VERSION 5.7 ;
  NOWIREEXTENSIONATPIN ON ;
  DIVIDERCHAR "/" ;
  BUSBITCHARS "[]" ;
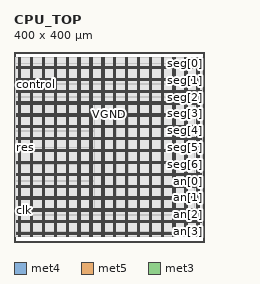
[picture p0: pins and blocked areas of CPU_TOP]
MACRO CPU_TOP
  CLASS BLOCK ;
  FOREIGN CPU_TOP ;
  ORIGIN 0.000 0.000 ;
  SIZE 400.000 BY 400.000 ;
  PIN VGND
    DIRECTION INOUT ;
    USE GROUND ;
    PORT
      LAYER met4 ;
        RECT 13.020 10.640 14.620 389.200 ;
    END
    PORT
      LAYER met4 ;
        RECT 38.020 10.640 39.620 389.200 ;
    END
    PORT
      LAYER met4 ;
        RECT 63.020 10.640 64.620 389.200 ;
    END
    PORT
      LAYER met4 ;
        RECT 88.020 10.640 89.620 389.200 ;
    END
    PORT
      LAYER met4 ;
        RECT 113.020 10.640 114.620 389.200 ;
    END
    PORT
      LAYER met4 ;
        RECT 138.020 10.640 139.620 389.200 ;
    END
    PORT
      LAYER met4 ;
        RECT 163.020 10.640 164.620 389.200 ;
    END
    PORT
      LAYER met4 ;
        RECT 188.020 10.640 189.620 389.200 ;
    END
    PORT
      LAYER met4 ;
        RECT 213.020 10.640 214.620 389.200 ;
    END
    PORT
      LAYER met4 ;
        RECT 238.020 10.640 239.620 389.200 ;
    END
    PORT
      LAYER met4 ;
        RECT 263.020 10.640 264.620 389.200 ;
    END
    PORT
      LAYER met4 ;
        RECT 288.020 10.640 289.620 389.200 ;
    END
    PORT
      LAYER met4 ;
        RECT 313.020 10.640 314.620 389.200 ;
    END
    PORT
      LAYER met4 ;
        RECT 338.020 10.640 339.620 389.200 ;
    END
    PORT
      LAYER met4 ;
        RECT 363.020 10.640 364.620 389.200 ;
    END
    PORT
      LAYER met4 ;
        RECT 388.020 10.640 389.620 389.200 ;
    END
    PORT
      LAYER met5 ;
        RECT 5.280 18.380 394.460 19.980 ;
    END
    PORT
      LAYER met5 ;
        RECT 5.280 43.380 394.460 44.980 ;
    END
    PORT
      LAYER met5 ;
        RECT 5.280 68.380 394.460 69.980 ;
    END
    PORT
      LAYER met5 ;
        RECT 5.280 93.380 394.460 94.980 ;
    END
    PORT
      LAYER met5 ;
        RECT 5.280 118.380 394.460 119.980 ;
    END
    PORT
      LAYER met5 ;
        RECT 5.280 143.380 394.460 144.980 ;
    END
    PORT
      LAYER met5 ;
        RECT 5.280 168.380 394.460 169.980 ;
    END
    PORT
      LAYER met5 ;
        RECT 5.280 193.380 394.460 194.980 ;
    END
    PORT
      LAYER met5 ;
        RECT 5.280 218.380 394.460 219.980 ;
    END
    PORT
      LAYER met5 ;
        RECT 5.280 243.380 394.460 244.980 ;
    END
    PORT
      LAYER met5 ;
        RECT 5.280 268.380 394.460 269.980 ;
    END
    PORT
      LAYER met5 ;
        RECT 5.280 293.380 394.460 294.980 ;
    END
    PORT
      LAYER met5 ;
        RECT 5.280 318.380 394.460 319.980 ;
    END
    PORT
      LAYER met5 ;
        RECT 5.280 343.380 394.460 344.980 ;
    END
    PORT
      LAYER met5 ;
        RECT 5.280 368.380 394.460 369.980 ;
    END
  END VGND
  PIN VPWR
    DIRECTION INOUT ;
    USE POWER ;
    PORT
      LAYER met4 ;
        RECT 9.720 10.640 11.320 389.200 ;
    END
    PORT
      LAYER met4 ;
        RECT 34.720 10.640 36.320 389.200 ;
    END
    PORT
      LAYER met4 ;
        RECT 59.720 10.640 61.320 389.200 ;
    END
    PORT
      LAYER met4 ;
        RECT 84.720 10.640 86.320 389.200 ;
    END
    PORT
      LAYER met4 ;
        RECT 109.720 10.640 111.320 389.200 ;
    END
    PORT
      LAYER met4 ;
        RECT 134.720 10.640 136.320 389.200 ;
    END
    PORT
      LAYER met4 ;
        RECT 159.720 10.640 161.320 389.200 ;
    END
    PORT
      LAYER met4 ;
        RECT 184.720 10.640 186.320 389.200 ;
    END
    PORT
      LAYER met4 ;
        RECT 209.720 10.640 211.320 389.200 ;
    END
    PORT
      LAYER met4 ;
        RECT 234.720 10.640 236.320 389.200 ;
    END
    PORT
      LAYER met4 ;
        RECT 259.720 10.640 261.320 389.200 ;
    END
    PORT
      LAYER met4 ;
        RECT 284.720 10.640 286.320 389.200 ;
    END
    PORT
      LAYER met4 ;
        RECT 309.720 10.640 311.320 389.200 ;
    END
    PORT
      LAYER met4 ;
        RECT 334.720 10.640 336.320 389.200 ;
    END
    PORT
      LAYER met4 ;
        RECT 359.720 10.640 361.320 389.200 ;
    END
    PORT
      LAYER met4 ;
        RECT 384.720 10.640 386.320 389.200 ;
    END
    PORT
      LAYER met5 ;
        RECT 5.280 15.080 394.460 16.680 ;
    END
    PORT
      LAYER met5 ;
        RECT 5.280 40.080 394.460 41.680 ;
    END
    PORT
      LAYER met5 ;
        RECT 5.280 65.080 394.460 66.680 ;
    END
    PORT
      LAYER met5 ;
        RECT 5.280 90.080 394.460 91.680 ;
    END
    PORT
      LAYER met5 ;
        RECT 5.280 115.080 394.460 116.680 ;
    END
    PORT
      LAYER met5 ;
        RECT 5.280 140.080 394.460 141.680 ;
    END
    PORT
      LAYER met5 ;
        RECT 5.280 165.080 394.460 166.680 ;
    END
    PORT
      LAYER met5 ;
        RECT 5.280 190.080 394.460 191.680 ;
    END
    PORT
      LAYER met5 ;
        RECT 5.280 215.080 394.460 216.680 ;
    END
    PORT
      LAYER met5 ;
        RECT 5.280 240.080 394.460 241.680 ;
    END
    PORT
      LAYER met5 ;
        RECT 5.280 265.080 394.460 266.680 ;
    END
    PORT
      LAYER met5 ;
        RECT 5.280 290.080 394.460 291.680 ;
    END
    PORT
      LAYER met5 ;
        RECT 5.280 315.080 394.460 316.680 ;
    END
    PORT
      LAYER met5 ;
        RECT 5.280 340.080 394.460 341.680 ;
    END
    PORT
      LAYER met5 ;
        RECT 5.280 365.080 394.460 366.680 ;
    END
  END VPWR
  PIN an[0]
    DIRECTION OUTPUT ;
    USE SIGNAL ;
    ANTENNADIFFAREA 0.340600 ;
    PORT
      LAYER met3 ;
        RECT 396.000 127.880 400.000 128.480 ;
    END
  END an[0]
  PIN an[1]
    DIRECTION OUTPUT ;
    USE SIGNAL ;
    ANTENNADIFFAREA 0.340600 ;
    PORT
      LAYER met3 ;
        RECT 396.000 92.520 400.000 93.120 ;
    END
  END an[1]
  PIN an[2]
    DIRECTION OUTPUT ;
    USE SIGNAL ;
    ANTENNADIFFAREA 0.340600 ;
    PORT
      LAYER met3 ;
        RECT 396.000 57.160 400.000 57.760 ;
    END
  END an[2]
  PIN an[3]
    DIRECTION OUTPUT ;
    USE SIGNAL ;
    ANTENNADIFFAREA 0.340600 ;
    PORT
      LAYER met3 ;
        RECT 396.000 21.800 400.000 22.400 ;
    END
  END an[3]
  PIN clk
    DIRECTION INPUT ;
    USE SIGNAL ;
    ANTENNAGATEAREA 0.852000 ;
    PORT
      LAYER met3 ;
        RECT 0.000 65.320 4.000 65.920 ;
    END
  END clk
  PIN control
    DIRECTION INPUT ;
    USE SIGNAL ;
    ANTENNAGATEAREA 0.159000 ;
    PORT
      LAYER met3 ;
        RECT 0.000 331.880 4.000 332.480 ;
    END
  END control
  PIN res
    DIRECTION INPUT ;
    USE SIGNAL ;
    ANTENNAGATEAREA 0.990000 ;
    PORT
      LAYER met3 ;
        RECT 0.000 198.600 4.000 199.200 ;
    END
  END res
  PIN seg[0]
    DIRECTION OUTPUT ;
    USE SIGNAL ;
    ANTENNADIFFAREA 0.340600 ;
    PORT
      LAYER met3 ;
        RECT 396.000 375.400 400.000 376.000 ;
    END
  END seg[0]
  PIN seg[1]
    DIRECTION OUTPUT ;
    USE SIGNAL ;
    ANTENNADIFFAREA 0.340600 ;
    PORT
      LAYER met3 ;
        RECT 396.000 340.040 400.000 340.640 ;
    END
  END seg[1]
  PIN seg[2]
    DIRECTION OUTPUT ;
    USE SIGNAL ;
    ANTENNADIFFAREA 0.340600 ;
    PORT
      LAYER met3 ;
        RECT 396.000 304.680 400.000 305.280 ;
    END
  END seg[2]
  PIN seg[3]
    DIRECTION OUTPUT ;
    USE SIGNAL ;
    ANTENNADIFFAREA 0.340600 ;
    PORT
      LAYER met3 ;
        RECT 396.000 269.320 400.000 269.920 ;
    END
  END seg[3]
  PIN seg[4]
    DIRECTION OUTPUT ;
    USE SIGNAL ;
    ANTENNADIFFAREA 0.340600 ;
    PORT
      LAYER met3 ;
        RECT 396.000 233.960 400.000 234.560 ;
    END
  END seg[4]
  PIN seg[5]
    DIRECTION OUTPUT ;
    USE SIGNAL ;
    ANTENNADIFFAREA 0.340600 ;
    PORT
      LAYER met3 ;
        RECT 396.000 198.600 400.000 199.200 ;
    END
  END seg[5]
  PIN seg[6]
    DIRECTION OUTPUT ;
    USE SIGNAL ;
    ANTENNADIFFAREA 0.340600 ;
    PORT
      LAYER met3 ;
        RECT 396.000 163.240 400.000 163.840 ;
    END
  END seg[6]
  OBS
      LAYER nwell ;
        RECT 5.330 10.795 394.410 389.150 ;
      LAYER li1 ;
        RECT 5.520 10.795 394.220 389.045 ;
      LAYER met1 ;
        RECT 4.210 10.640 394.520 389.200 ;
      LAYER met2 ;
        RECT 4.230 10.695 392.750 389.145 ;
      LAYER met3 ;
        RECT 3.990 376.400 396.000 389.125 ;
        RECT 3.990 375.000 395.600 376.400 ;
        RECT 3.990 341.040 396.000 375.000 ;
        RECT 3.990 339.640 395.600 341.040 ;
        RECT 3.990 332.880 396.000 339.640 ;
        RECT 4.400 331.480 396.000 332.880 ;
        RECT 3.990 305.680 396.000 331.480 ;
        RECT 3.990 304.280 395.600 305.680 ;
        RECT 3.990 270.320 396.000 304.280 ;
        RECT 3.990 268.920 395.600 270.320 ;
        RECT 3.990 234.960 396.000 268.920 ;
        RECT 3.990 233.560 395.600 234.960 ;
        RECT 3.990 199.600 396.000 233.560 ;
        RECT 4.400 198.200 395.600 199.600 ;
        RECT 3.990 164.240 396.000 198.200 ;
        RECT 3.990 162.840 395.600 164.240 ;
        RECT 3.990 128.880 396.000 162.840 ;
        RECT 3.990 127.480 395.600 128.880 ;
        RECT 3.990 93.520 396.000 127.480 ;
        RECT 3.990 92.120 395.600 93.520 ;
        RECT 3.990 66.320 396.000 92.120 ;
        RECT 4.400 64.920 396.000 66.320 ;
        RECT 3.990 58.160 396.000 64.920 ;
        RECT 3.990 56.760 395.600 58.160 ;
        RECT 3.990 22.800 396.000 56.760 ;
        RECT 3.990 21.400 395.600 22.800 ;
        RECT 3.990 10.715 396.000 21.400 ;
      LAYER met4 ;
        RECT 169.575 66.135 184.320 292.225 ;
        RECT 186.720 66.135 187.620 292.225 ;
        RECT 190.020 66.135 209.320 292.225 ;
        RECT 211.720 66.135 212.620 292.225 ;
        RECT 215.020 66.135 234.320 292.225 ;
        RECT 236.720 66.135 237.620 292.225 ;
        RECT 240.020 66.135 259.320 292.225 ;
        RECT 261.720 66.135 262.620 292.225 ;
        RECT 265.020 66.135 284.320 292.225 ;
        RECT 286.720 66.135 287.620 292.225 ;
        RECT 290.020 66.135 309.320 292.225 ;
        RECT 311.720 66.135 312.620 292.225 ;
        RECT 315.020 66.135 334.320 292.225 ;
        RECT 336.720 66.135 337.620 292.225 ;
        RECT 340.020 66.135 359.320 292.225 ;
        RECT 361.720 66.135 362.620 292.225 ;
        RECT 365.020 66.135 379.665 292.225 ;
  END
END CPU_TOP
END LIBRARY

